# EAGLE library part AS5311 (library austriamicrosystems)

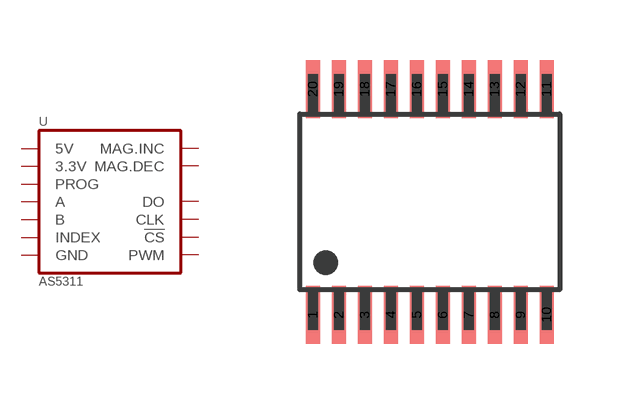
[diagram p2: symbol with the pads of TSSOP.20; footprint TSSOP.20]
Designator prefix -

## AS5311  [TSSOP.20]
2  MAG.INC
3  MAG.DEC
4  A
5  B
7  INDEX
8  GND
9  PROG
12  DO
13  CLK
14  !CS
15  PWM
18  3.3V
19  5V

## Footprint TSSOP.20 (pad centres in mm)
smd 0.35 x 1.45: 1 -2.925,-2.825; 2 -2.275,-2.825; 3 -1.625,-2.825; 4 -0.975,-2.825; 5 -0.325,-2.825; 6 0.325,-2.825; 7 0.975,-2.825; 8 1.625,-2.825; 9 2.275,-2.825; 10 2.925,-2.825; 11 2.925,2.825; 12 2.275,2.825; 13 1.625,2.825; 14 0.975,2.825; 15 0.325,2.825; 16 -0.325,2.825; 17 -0.975,2.825; 18 -1.625,2.825; 19 -2.275,2.825; 20 -2.925,2.825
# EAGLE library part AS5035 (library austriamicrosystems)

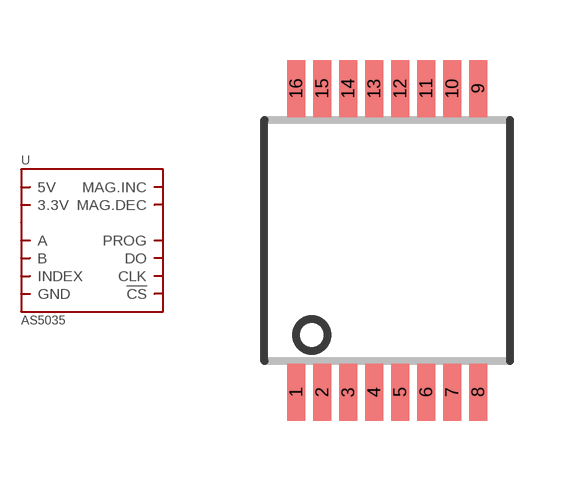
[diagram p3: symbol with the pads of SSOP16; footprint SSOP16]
Designator prefix -

## AS5035  [SSOP16]
1  MAG.INC
2  MAG.DEC
3  A
4  B
6  INDEX
7  GND
8  PROG
9  DO
10  CLK
11  !CS
15  3.3V
16  5V

## Footprint SSOP16 (pad centres in mm)
Small Shrink Outline Package SSOP 16 (5.3mm x 6.2mm) Source: www.austriamicrosystems.com .. AS5040DataSheetRev12.pdf
smd 0.46 x 1.43: 1 -2.275,-3.795; 2 -1.625,-3.795; 3 -0.975,-3.795; 4 -0.325,-3.795; 5 0.325,-3.795; 6 0.975,-3.795; 7 1.625,-3.795; 8 2.275,-3.795; 9 2.275,3.795; 10 1.625,3.795; 11 0.975,3.795; 12 0.325,3.795; 13 -0.325,3.795; 14 -0.975,3.795; 15 -1.625,3.795; 16 -2.275,3.795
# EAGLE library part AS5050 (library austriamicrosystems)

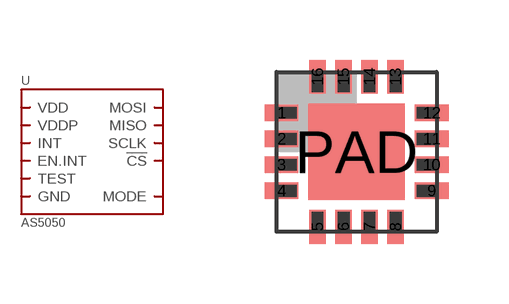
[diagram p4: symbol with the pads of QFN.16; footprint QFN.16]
Designator prefix -

## AS5050.QFN  [QFN.16]
1  MOSI
2  MISO
3  SCLK
4  !CS
9  TEST
10  EN.INT
11  VDDP
12  VDD
13  GND
14  MODE
15  INT

## Footprint QFN.16 (pad centres in mm)
smd 0.85 x 0.42: 1 -1.875,0.975; 2 -1.875,0.325; 3 -1.875,-0.325; 4 -1.875,-0.975; 9 1.875,-0.975; 10 1.875,-0.325; 11 1.875,0.325; 12 1.875,0.975
smd 0.42 x 0.85: 5 -0.975,-1.875; 6 -0.325,-1.875; 7 0.325,-1.875; 8 0.975,-1.875; 13 0.975,1.875; 14 0.325,1.875; 15 -0.325,1.875; 16 -0.975,1.875
smd 2.4 x 2.4: PAD 0,0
